One B-rep face of a CAD part: STEP entity #57198.
In plain terms, the planar face has unit normal (0, 0, 1).
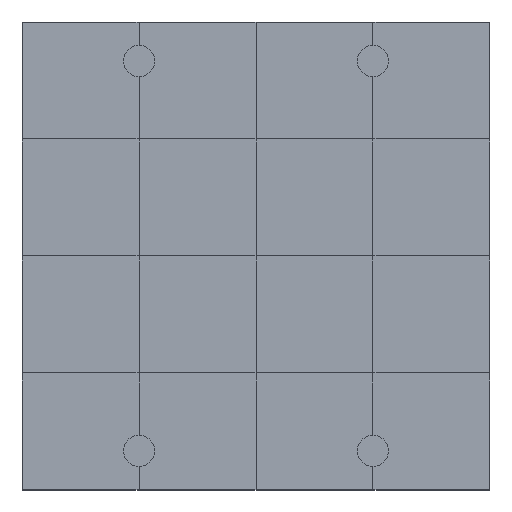
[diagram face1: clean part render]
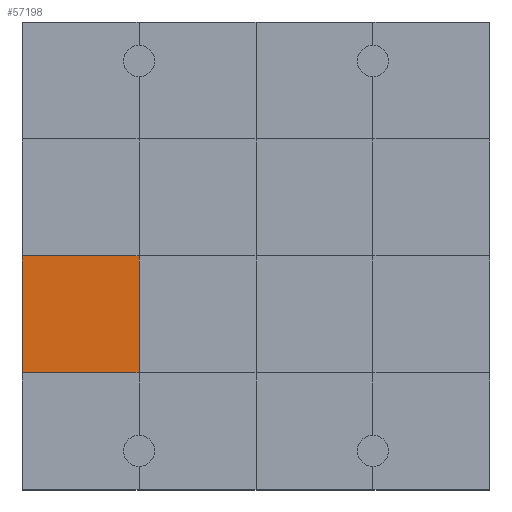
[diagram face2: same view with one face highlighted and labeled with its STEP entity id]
Its self-contained STEP definition (entity closure, numbers rounded to 3 decimals):
#56748 = VERTEX_POINT('',#56749);
#56749 = CARTESIAN_POINT('',(0.,3.,1.2));
#56763 = PLANE('',#56764);
#56764 = AXIS2_PLACEMENT_3D('',#56765,#56766,#56767);
#56765 = CARTESIAN_POINT('',(0.,3.,0.));
#56766 = DIRECTION('',(1.,0.,-0.));
#56767 = DIRECTION('',(0.,0.,1.));
#56789 = PLANE('',#56790);
#56790 = AXIS2_PLACEMENT_3D('',#56791,#56792,#56793);
#56791 = CARTESIAN_POINT('',(0.,0.,1.2));
#56792 = DIRECTION('',(0.,0.,1.));
#56793 = DIRECTION('',(1.,0.,-0.));
#56940 = VERTEX_POINT('',#56941);
#56941 = CARTESIAN_POINT('',(3.,3.,1.2));
#56962 = EDGE_CURVE('',#56748,#56940,#56963,.T.);
#56963 = SURFACE_CURVE('',#56964,(#56968,#56975),.PCURVE_S1.);
#56964 = LINE('',#56965,#56966);
#56965 = CARTESIAN_POINT('',(0.,3.,1.2));
#56966 = VECTOR('',#56967,1.);
#56967 = DIRECTION('',(1.,0.,-0.));
#56968 = PCURVE('',#56789,#56969);
#56969 = DEFINITIONAL_REPRESENTATION('',(#56970),#56974);
#56970 = LINE('',#56971,#56972);
#56971 = CARTESIAN_POINT('',(0.,3.));
#56972 = VECTOR('',#56973,1.);
#56973 = DIRECTION('',(1.,0.));
#56974 = ( GEOMETRIC_REPRESENTATION_CONTEXT(2) 
PARAMETRIC_REPRESENTATION_CONTEXT() REPRESENTATION_CONTEXT('2D SPACE',''
  ) );
#56975 = PCURVE('',#56976,#56981);
#56976 = PLANE('',#56977);
#56977 = AXIS2_PLACEMENT_3D('',#56978,#56979,#56980);
#56978 = CARTESIAN_POINT('',(0.,3.,1.2));
#56979 = DIRECTION('',(0.,0.,1.));
#56980 = DIRECTION('',(1.,0.,-0.));
#56981 = DEFINITIONAL_REPRESENTATION('',(#56982),#56986);
#56982 = LINE('',#56983,#56984);
#56983 = CARTESIAN_POINT('',(0.,0.));
#56984 = VECTOR('',#56985,1.);
#56985 = DIRECTION('',(1.,0.));
#56986 = ( GEOMETRIC_REPRESENTATION_CONTEXT(2) 
PARAMETRIC_REPRESENTATION_CONTEXT() REPRESENTATION_CONTEXT('2D SPACE',''
  ) );
#57021 = VERTEX_POINT('',#57022);
#57022 = CARTESIAN_POINT('',(0.,6.,1.2));
#57048 = EDGE_CURVE('',#56748,#57021,#57049,.T.);
#57049 = SURFACE_CURVE('',#57050,(#57054,#57061),.PCURVE_S1.);
#57050 = LINE('',#57051,#57052);
#57051 = CARTESIAN_POINT('',(0.,3.,1.2));
#57052 = VECTOR('',#57053,1.);
#57053 = DIRECTION('',(-0.,1.,0.));
#57054 = PCURVE('',#56763,#57055);
#57055 = DEFINITIONAL_REPRESENTATION('',(#57056),#57060);
#57056 = LINE('',#57057,#57058);
#57057 = CARTESIAN_POINT('',(1.2,0.));
#57058 = VECTOR('',#57059,1.);
#57059 = DIRECTION('',(0.,-1.));
#57060 = ( GEOMETRIC_REPRESENTATION_CONTEXT(2) 
PARAMETRIC_REPRESENTATION_CONTEXT() REPRESENTATION_CONTEXT('2D SPACE',''
  ) );
#57061 = PCURVE('',#56976,#57062);
#57062 = DEFINITIONAL_REPRESENTATION('',(#57063),#57067);
#57063 = LINE('',#57064,#57065);
#57064 = CARTESIAN_POINT('',(0.,0.));
#57065 = VECTOR('',#57066,1.);
#57066 = DIRECTION('',(0.,1.));
#57067 = ( GEOMETRIC_REPRESENTATION_CONTEXT(2) 
PARAMETRIC_REPRESENTATION_CONTEXT() REPRESENTATION_CONTEXT('2D SPACE',''
  ) );
#57198 = ADVANCED_FACE('',(#57199),#56976,.T.);
#57199 = FACE_BOUND('',#57200,.T.);
#57200 = EDGE_LOOP('',(#57201,#57202,#57203,#57231));
#57201 = ORIENTED_EDGE('',*,*,#57048,.F.);
#57202 = ORIENTED_EDGE('',*,*,#56962,.T.);
#57203 = ORIENTED_EDGE('',*,*,#57204,.T.);
#57204 = EDGE_CURVE('',#56940,#57205,#57207,.T.);
#57205 = VERTEX_POINT('',#57206);
#57206 = CARTESIAN_POINT('',(3.,6.,1.2));
#57207 = SURFACE_CURVE('',#57208,(#57212,#57219),.PCURVE_S1.);
#57208 = LINE('',#57209,#57210);
#57209 = CARTESIAN_POINT('',(3.,3.,1.2));
#57210 = VECTOR('',#57211,1.);
#57211 = DIRECTION('',(-0.,1.,0.));
#57212 = PCURVE('',#56976,#57213);
#57213 = DEFINITIONAL_REPRESENTATION('',(#57214),#57218);
#57214 = LINE('',#57215,#57216);
#57215 = CARTESIAN_POINT('',(3.,0.));
#57216 = VECTOR('',#57217,1.);
#57217 = DIRECTION('',(0.,1.));
#57218 = ( GEOMETRIC_REPRESENTATION_CONTEXT(2) 
PARAMETRIC_REPRESENTATION_CONTEXT() REPRESENTATION_CONTEXT('2D SPACE',''
  ) );
#57219 = PCURVE('',#57220,#57225);
#57220 = PLANE('',#57221);
#57221 = AXIS2_PLACEMENT_3D('',#57222,#57223,#57224);
#57222 = CARTESIAN_POINT('',(3.,3.,1.2));
#57223 = DIRECTION('',(0.,0.,1.));
#57224 = DIRECTION('',(1.,0.,-0.));
#57225 = DEFINITIONAL_REPRESENTATION('',(#57226),#57230);
#57226 = LINE('',#57227,#57228);
#57227 = CARTESIAN_POINT('',(0.,0.));
#57228 = VECTOR('',#57229,1.);
#57229 = DIRECTION('',(0.,1.));
#57230 = ( GEOMETRIC_REPRESENTATION_CONTEXT(2) 
PARAMETRIC_REPRESENTATION_CONTEXT() REPRESENTATION_CONTEXT('2D SPACE',''
  ) );
#57231 = ORIENTED_EDGE('',*,*,#57232,.F.);
#57232 = EDGE_CURVE('',#57021,#57205,#57233,.T.);
#57233 = SURFACE_CURVE('',#57234,(#57238,#57245),.PCURVE_S1.);
#57234 = LINE('',#57235,#57236);
#57235 = CARTESIAN_POINT('',(0.,6.,1.2));
#57236 = VECTOR('',#57237,1.);
#57237 = DIRECTION('',(1.,0.,-0.));
#57238 = PCURVE('',#56976,#57239);
#57239 = DEFINITIONAL_REPRESENTATION('',(#57240),#57244);
#57240 = LINE('',#57241,#57242);
#57241 = CARTESIAN_POINT('',(0.,3.));
#57242 = VECTOR('',#57243,1.);
#57243 = DIRECTION('',(1.,0.));
#57244 = ( GEOMETRIC_REPRESENTATION_CONTEXT(2) 
PARAMETRIC_REPRESENTATION_CONTEXT() REPRESENTATION_CONTEXT('2D SPACE',''
  ) );
#57245 = PCURVE('',#57246,#57251);
#57246 = PLANE('',#57247);
#57247 = AXIS2_PLACEMENT_3D('',#57248,#57249,#57250);
#57248 = CARTESIAN_POINT('',(0.,6.,1.2));
#57249 = DIRECTION('',(0.,0.,1.));
#57250 = DIRECTION('',(1.,0.,-0.));
#57251 = DEFINITIONAL_REPRESENTATION('',(#57252),#57256);
#57252 = LINE('',#57253,#57254);
#57253 = CARTESIAN_POINT('',(0.,0.));
#57254 = VECTOR('',#57255,1.);
#57255 = DIRECTION('',(1.,0.));
#57256 = ( GEOMETRIC_REPRESENTATION_CONTEXT(2) 
PARAMETRIC_REPRESENTATION_CONTEXT() REPRESENTATION_CONTEXT('2D SPACE',''
  ) );
